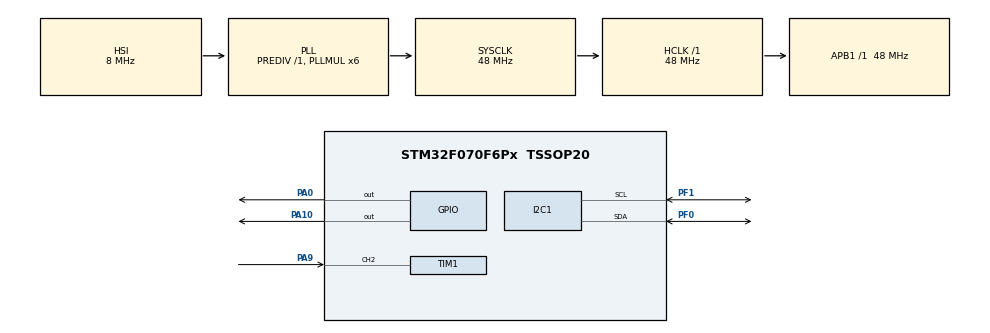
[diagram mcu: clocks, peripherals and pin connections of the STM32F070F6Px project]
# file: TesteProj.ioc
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Mcu.Family=STM32F0
Mcu.Name=STM32F070F6Px
Mcu.Package=TSSOP20
PA0.Signal=GPIO_Output
PA10.Signal=GPIO_Output
PA13.Mode=Serial_Wire
PA13.Signal=SYS_SWDIO
PA14.Mode=Serial_Wire
PA14.Signal=SYS_SWCLK
PA9.Signal=S_TIM1_CH2
PF0-OSC_IN.Mode=I2C
PF0-OSC_IN.Signal=I2C1_SDA
PF1-OSC_OUT.Mode=I2C
PF1-OSC_OUT.Signal=I2C1_SCL
ProjectManager.HeapSize=0x200
ProjectManager.StackSize=0x400
ProjectManager.TargetToolchain=STM32CubeIDE
RCC.AHBFreq_Value=48000000
RCC.APB1Freq_Value=48000000
RCC.APB1TimFreq_Value=48000000
RCC.HCLKFreq_Value=48000000
RCC.PLLMUL=RCC_PLL_MUL6
RCC.SYSCLKFreq_VALUE=48000000
RCC.SYSCLKSource=RCC_SYSCLKSOURCE_PLLCLK
SH.S_TIM1_CH2.0=TIM1_CH2,Input_Capture2_from_TI2
TIM1.Channel-Input_Capture2_from_TI2=TIM_CHANNEL_2
TIM1.Prescaler=47
VP_TIM1_VS_ClockSourceINT.Mode=Internal
board=custom

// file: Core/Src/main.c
/* USER CODE BEGIN Header */
/**
  ******************************************************************************
  * @file           : main.c
  * @brief          : Main program body
  ******************************************************************************
  * @attention
  *
  * Copyright (c) 2023 STMicroelectronics.
  * All rights reserved.
  *
  * This software is licensed under terms that can be found in the LICENSE file
  * in the root directory of this software component.
  * If no LICENSE file comes with this software, it is provided AS-IS.
  *
  ******************************************************************************
  */
/* USER CODE END Header */
#include "main.h"

I2C_HandleTypeDef hi2c1;

TIM_HandleTypeDef htim1;

/* USER CODE BEGIN PV */
uint32_t valsubida = 0;
uint32_t valdescida = 0;
uint16_t distance  = 0;
int16_t Accel_X_RAW = 0;
int16_t Accel_Y_RAW = 0;
int16_t Accel_Z_RAW = 0;
float Ax,Ay,Az;
//int16_t xacc = 0;
/* USER CODE END PV */

void SystemClock_Config(void);
static void MX_GPIO_Init(void);
static void MX_TIM1_Init(void);
static void MX_I2C1_Init(void);

/* USER CODE BEGIN 0 */
#define MPU6050_ADDR 0xD0
#define SMPLRT_DIV_REG 0x19
#define ACCEL_CONFIG_REG 0x1C
#define ACCEL_XOUT_H_REG 0x3B
#define PWR_MGMT_1_REG 0x6B
#define WHO_AM_I_REG 0x75
void MPU6050_Init (void)
{
	uint8_t check;
	uint8_t Data;
	HAL_I2C_Mem_Read (&hi2c1, MPU6050_ADDR,WHO_AM_I_REG,1, &check, 1, 1000);

	if (check == 104)
	{
		// power management register 0X6B we should write all 0's to wake the sensor up
		Data = 0;
		HAL_I2C_Mem_Write(&hi2c1, MPU6050_ADDR, PWR_MGMT_1_REG, 1,&Data, 1, 1000);

		// Set DATA RATE of 1KHz by writing SMPLRT_DIV register
		Data = 0x07;
		HAL_I2C_Mem_Write(&hi2c1, MPU6050_ADDR, SMPLRT_DIV_REG, 1, &Data, 1, 1000);
		Data = 0x00;
		HAL_I2C_Mem_Write(&hi2c1, MPU6050_ADDR, ACCEL_CONFIG_REG, 1, &Data, 1, 1000);
	}

}

void MPU6050_Read_Accel (void)
{
	uint8_t Rec_Data[6];

	// Read 6 BYTES of data starting from ACCEL_XOUT_H register

	HAL_I2C_Mem_Read (&hi2c1, MPU6050_ADDR, ACCEL_XOUT_H_REG, 1, Rec_Data, 6, 1000);

	Accel_X_RAW = (int16_t)(Rec_Data[0] << 8 | Rec_Data [1]);
	Accel_Y_RAW = (int16_t)(Rec_Data[2] << 8 | Rec_Data [3]);
	Accel_Z_RAW = (int16_t)(Rec_Data[4] << 8 | Rec_Data [5]);

	/*** convert the RAW values into acceleration in 'g'
	     we have to divide according to the Full scale value set in FS_SEL
	     I have configured FS_SEL = 0. So I am dividing by 16384.0
	     for more details check ACCEL_CONFIG Register              ****/

	Ax = Accel_X_RAW/16384.0;
	Ay = Accel_Y_RAW/16384.0;
	Az = Accel_Z_RAW/16384.0;
}
/* USER CODE END 0 */

int main(void)
{

  /* MCU Configuration--------------------------------------------------------*/

  /* Reset of all peripherals, Initializes the Flash interface and the Systick. */
  HAL_Init();

  /* Configure the system clock */
  SystemClock_Config();

  /* Initialize all configured peripherals */
  MX_GPIO_Init();
  MX_TIM1_Init();
  MX_I2C1_Init();
  /* USER CODE BEGIN 2 */
  HAL_TIM_Base_Start(&htim1);
  HAL_GPIO_WritePin(GPIOA, GPIO_PIN_10, GPIO_PIN_RESET);
  MPU6050_Init();
  /* USER CODE END 2 */

  /* Infinite loop */
  /* USER CODE BEGIN WHILE */
  while (1)
  {
	  HAL_GPIO_WritePin(GPIOA, GPIO_PIN_10, GPIO_PIN_SET);
	  __HAL_TIM_SET_COUNTER(&htim1, 0);
	  while (__HAL_TIM_GET_COUNTER (&htim1) < 10);  // wait for 10 us
	  HAL_GPIO_WritePin(GPIOA, GPIO_PIN_10, GPIO_PIN_RESET);
	  while (!(HAL_GPIO_ReadPin (GPIOA, GPIO_PIN_9)));
	  valsubida = __HAL_TIM_GET_COUNTER (&htim1);
	  while ((HAL_GPIO_ReadPin(GPIOA, GPIO_PIN_9)));
	  valdescida = __HAL_TIM_GET_COUNTER (&htim1);
	  distance = (valdescida-valsubida)* 0.034/2;
	  MPU6050_Read_Accel();
	  if(distance <= 30 + Ax*100){
		  HAL_GPIO_WritePin(GPIOA, GPIO_PIN_0, GPIO_PIN_SET);
	  }
	  else{
		  HAL_GPIO_WritePin(GPIOA, GPIO_PIN_0, GPIO_PIN_RESET);
	  }
    /* USER CODE END WHILE */

  }
}

void SystemClock_Config(void)
{
  RCC_OscInitTypeDef RCC_OscInitStruct = {0};
  RCC_ClkInitTypeDef RCC_ClkInitStruct = {0};
  RCC_PeriphCLKInitTypeDef PeriphClkInit = {0};

  /** Initializes the RCC Oscillators according to the specified parameters
  * in the RCC_OscInitTypeDef structure.
  */
  RCC_OscInitStruct.OscillatorType = RCC_OSCILLATORTYPE_HSI;
  RCC_OscInitStruct.HSIState = RCC_HSI_ON;
  RCC_OscInitStruct.HSICalibrationValue = RCC_HSICALIBRATION_DEFAULT;
  RCC_OscInitStruct.PLL.PLLState = RCC_PLL_ON;
  RCC_OscInitStruct.PLL.PLLSource = RCC_PLLSOURCE_HSI;
  RCC_OscInitStruct.PLL.PLLMUL = RCC_PLL_MUL6;
  RCC_OscInitStruct.PLL.PREDIV = RCC_PREDIV_DIV1;
  if (HAL_RCC_OscConfig(&RCC_OscInitStruct) != HAL_OK)
  {
    Error_Handler();
  }

  /** Initializes the CPU, AHB and APB buses clocks
  */
  RCC_ClkInitStruct.ClockType = RCC_CLOCKTYPE_HCLK|RCC_CLOCKTYPE_SYSCLK
                              |RCC_CLOCKTYPE_PCLK1;
  RCC_ClkInitStruct.SYSCLKSource = RCC_SYSCLKSOURCE_PLLCLK;
  RCC_ClkInitStruct.AHBCLKDivider = RCC_SYSCLK_DIV1;
  RCC_ClkInitStruct.APB1CLKDivider = RCC_HCLK_DIV1;

  if (HAL_RCC_ClockConfig(&RCC_ClkInitStruct, FLASH_LATENCY_1) != HAL_OK)
  {
    Error_Handler();
  }
  PeriphClkInit.PeriphClockSelection = RCC_PERIPHCLK_I2C1;
  PeriphClkInit.I2c1ClockSelection = RCC_I2C1CLKSOURCE_HSI;
  if (HAL_RCCEx_PeriphCLKConfig(&PeriphClkInit) != HAL_OK)
  {
    Error_Handler();
  }
}

static void MX_I2C1_Init(void)
{

  hi2c1.Instance = I2C1;
  hi2c1.Init.Timing = 0x2000090E;
  hi2c1.Init.OwnAddress1 = 0;
  hi2c1.Init.AddressingMode = I2C_ADDRESSINGMODE_7BIT;
  hi2c1.Init.DualAddressMode = I2C_DUALADDRESS_DISABLE;
  hi2c1.Init.OwnAddress2 = 0;
  hi2c1.Init.OwnAddress2Masks = I2C_OA2_NOMASK;
  hi2c1.Init.GeneralCallMode = I2C_GENERALCALL_DISABLE;
  hi2c1.Init.NoStretchMode = I2C_NOSTRETCH_DISABLE;
  if (HAL_I2C_Init(&hi2c1) != HAL_OK)
  {
    Error_Handler();
  }

  /** Configure Analogue filter
  */
  if (HAL_I2CEx_ConfigAnalogFilter(&hi2c1, I2C_ANALOGFILTER_ENABLE) != HAL_OK)
  {
    Error_Handler();
  }

  /** Configure Digital filter
  */
  if (HAL_I2CEx_ConfigDigitalFilter(&hi2c1, 0) != HAL_OK)
  {
    Error_Handler();
  }

}

static void MX_TIM1_Init(void)
{

  TIM_ClockConfigTypeDef sClockSourceConfig = {0};
  TIM_MasterConfigTypeDef sMasterConfig = {0};
  TIM_IC_InitTypeDef sConfigIC = {0};

  htim1.Instance = TIM1;
  htim1.Init.Prescaler = 47;
  htim1.Init.CounterMode = TIM_COUNTERMODE_UP;
  htim1.Init.Period = 65535;
  htim1.Init.ClockDivision = TIM_CLOCKDIVISION_DIV1;
  htim1.Init.RepetitionCounter = 0;
  htim1.Init.AutoReloadPreload = TIM_AUTORELOAD_PRELOAD_DISABLE;
  if (HAL_TIM_Base_Init(&htim1) != HAL_OK)
  {
    Error_Handler();
  }
  sClockSourceConfig.ClockSource = TIM_CLOCKSOURCE_INTERNAL;
  if (HAL_TIM_ConfigClockSource(&htim1, &sClockSourceConfig) != HAL_OK)
  {
    Error_Handler();
  }
  if (HAL_TIM_IC_Init(&htim1) != HAL_OK)
  {
    Error_Handler();
  }
  sMasterConfig.MasterOutputTrigger = TIM_TRGO_RESET;
  sMasterConfig.MasterSlaveMode = TIM_MASTERSLAVEMODE_DISABLE;
  if (HAL_TIMEx_MasterConfigSynchronization(&htim1, &sMasterConfig) != HAL_OK)
  {
    Error_Handler();
  }
  sConfigIC.ICPolarity = TIM_INPUTCHANNELPOLARITY_RISING;
  sConfigIC.ICSelection = TIM_ICSELECTION_DIRECTTI;
  sConfigIC.ICPrescaler = TIM_ICPSC_DIV1;
  sConfigIC.ICFilter = 0;
  if (HAL_TIM_IC_ConfigChannel(&htim1, &sConfigIC, TIM_CHANNEL_2) != HAL_OK)
  {
    Error_Handler();
  }

}

static void MX_GPIO_Init(void)
{
  GPIO_InitTypeDef GPIO_InitStruct = {0};

  /* GPIO Ports Clock Enable */
  __HAL_RCC_GPIOF_CLK_ENABLE();
  __HAL_RCC_GPIOA_CLK_ENABLE();

  /*Configure GPIO pin Output Level */
  HAL_GPIO_WritePin(GPIOA, GPIO_PIN_0|GPIO_PIN_1|GPIO_PIN_2|GPIO_PIN_10, GPIO_PIN_RESET);

  /*Configure GPIO pins : PA0 PA1 PA2 PA10 */
  GPIO_InitStruct.Pin = GPIO_PIN_0|GPIO_PIN_1|GPIO_PIN_2|GPIO_PIN_10;
  GPIO_InitStruct.Mode = GPIO_MODE_OUTPUT_PP;
  GPIO_InitStruct.Pull = GPIO_NOPULL;
  GPIO_InitStruct.Speed = GPIO_SPEED_FREQ_LOW;
  HAL_GPIO_Init(GPIOA, &GPIO_InitStruct);

}

void Error_Handler(void)
{
  __disable_irq();
  while (1)
  {
  }
}
